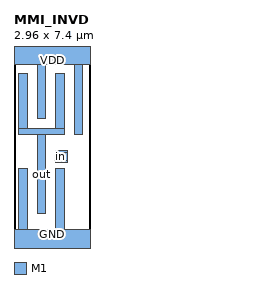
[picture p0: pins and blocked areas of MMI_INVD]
MACRO MMI_INVD
	CLASS CORE ;
	FOREIGN MMI_INVD 0 0 ;
	SIZE 2.96 BY 7.4 ;
	SYMMETRY X Y ;
	SITE CORE1 ;
	PIN out
		DIRECTION output ;
		USE SIGNAL ;
		PORT
			LAYER M1 ;
			RECT 0.18 4.405 0.52 6.55 ;
			LAYER M1 ;
			RECT 1.62 4.405 1.96 6.55 ;
			LAYER M1 ;
			RECT 0.18 4.175 1.96 4.405 ;
			LAYER M1 ;
			RECT 0.89 4.17 1.24 4.175 ;
			LAYER M1 ;
			RECT 0.9 1.115 1.24 4.17 ;
		END
		AntennaDiffArea 3.4977 ;
	END out
	PIN GND
		DIRECTION inout ;
		USE GROUND ;
		PORT
			LAYER M1 ;
			RECT 0.18 0.5 0.52 2.875 ;
			LAYER M1 ;
			RECT 1.62 0.5 1.96 2.875 ;
			LAYER M1 ;
			RECT 0 -0.5 2.96 0.5 ;
		END
	END GND
	PIN VDD
		DIRECTION inout ;
		USE POWER ;
		PORT
			LAYER M1 ;
			RECT 0 6.9 2.96 7.9 ;
			LAYER M1 ;
			RECT 0.9 4.795 1.24 6.9 ;
			LAYER M1 ;
			RECT 2.34 4.175 2.68 6.9 ;
		END
	END VDD
	PIN in
		DIRECTION input ;
		USE SIGNAL ;
		PORT
			LAYER M1 ;
			RECT 1.625 3.5 2.075 3.555 ;
			LAYER M1 ;
			RECT 1.56 3.16 2.075 3.5 ;
			LAYER M1 ;
			RECT 1.625 3.105 2.075 3.16 ;
		END
		AntennaGateArea 1.9881 ;
	END in
	OBS
	END
END MMI_INVD
